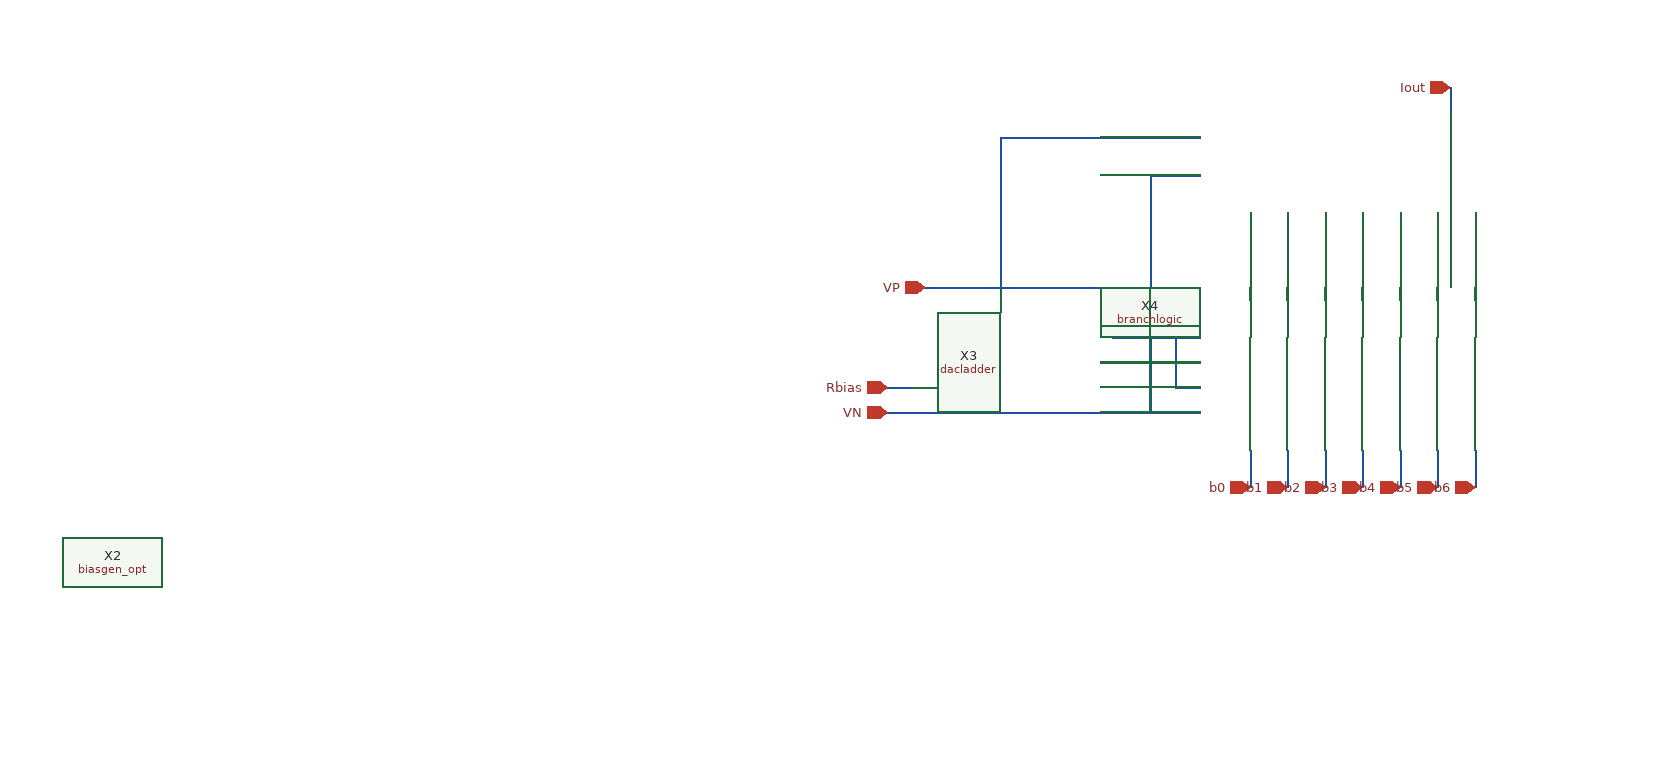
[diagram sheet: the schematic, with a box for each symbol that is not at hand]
v {xschem version=2.9.9 file_version=1.2 }
G {}
K {}
V {}
S {}
E {}
N 1600 -540 1600 -470 { lab=#net1}
N 1570 -540 1570 -470 { lab=#net2}
N 1540 -540 1540 -470 { lab=#net3}
N 1510 -540 1510 -470 { lab=#net4}
N 1480 -540 1480 -470 { lab=#net5}
N 1450 -540 1450 -470 { lab=#net6}
N 1420 -540 1420 -470 { lab=#net7}
N 1580 -640 1580 -620 { lab=Iout}
N 1420 -350 1420 -320 { lab=b0}
N 1450 -350 1450 -320 { lab=b1}
N 1480 -350 1480 -320 { lab=b2}
N 1510 -350 1510 -320 { lab=b3}
N 1540 -350 1540 -320 { lab=b4}
N 1570 -350 1570 -320 { lab=b5}
N 1600 -350 1600 -320 { lab=b6}
N 1130 -400 1150 -400 { lab=Rbias}
N 1300 -420 1380 -420 { lab=#net8}
N 1300 -450 1310 -450 { lab=#net9}
N 1310 -450 1310 -440 { lab=#net9}
N 1310 -440 1380 -440 { lab=#net9}
N 1360 -600 1380 -600 { lab=VP}
N 1360 -570 1380 -570 { lab=VN}
N 1370 -380 1380 -380 { lab=VN}
N 1360 -400 1380 -400 { lab=VP}
N 1180 -380 1370 -380 { lab=VN}
N 1360 -480 1360 -400 { lab=VP}
N 1180 -480 1360 -480 { lab=VP}
N 1160 -480 1180 -480 { lab=VP}
N 1220 -600 1360 -600 { lab=VP}
N 1220 -600 1220 -480 { lab=VP}
N 1130 -380 1180 -380 { lab=VN}
N 1340 -570 1360 -570 { lab=VN}
N 1340 -570 1340 -380 { lab=VN}
C {devices/iopin.sym} 1160 -480 2 0 {name=p1 lab=VP}
C {devices/iopin.sym} 1130 -380 2 0 {name=p2 lab=VN}
C {devices/iopin.sym} 1130 -400 2 0 {name=p3 lab=Rbias}
C {devices/iopin.sym} 1580 -640 3 0 {name=p4 lab=Iout}
C {devices/ipin.sym} 1420 -320 3 0 {name=p5 lab=b0}
C {devices/ipin.sym} 1450 -320 3 0 {name=p6 lab=b1}
C {devices/ipin.sym} 1480 -320 3 0 {name=p7 lab=b2}
C {devices/ipin.sym} 1510 -320 3 0 {name=p8 lab=b3}
C {devices/ipin.sym} 1540 -320 3 0 {name=p9 lab=b4}
C {devices/ipin.sym} 1570 -320 3 0 {name=p11 lab=b5}
C {devices/ipin.sym} 1600 -320 3 0 {name=p10 lab=b6}
C {/home/jonah/VLSI/VLSI-MP4/design-files/dacladder.sym} 1000 -320 0 0 {name=X3}
C {/home/jonah/VLSI/VLSI-MP4/design-files/opt/biasgen_opt.sym} 510 -260 0 0 {name=X2}
C {/home/jonah/VLSI/VLSI-MP4/design-files/branchlogic.sym} 1200 -170 0 0 {name=X4}
